VERSION 5.7 ;
BUSBITCHARS "[]" ;
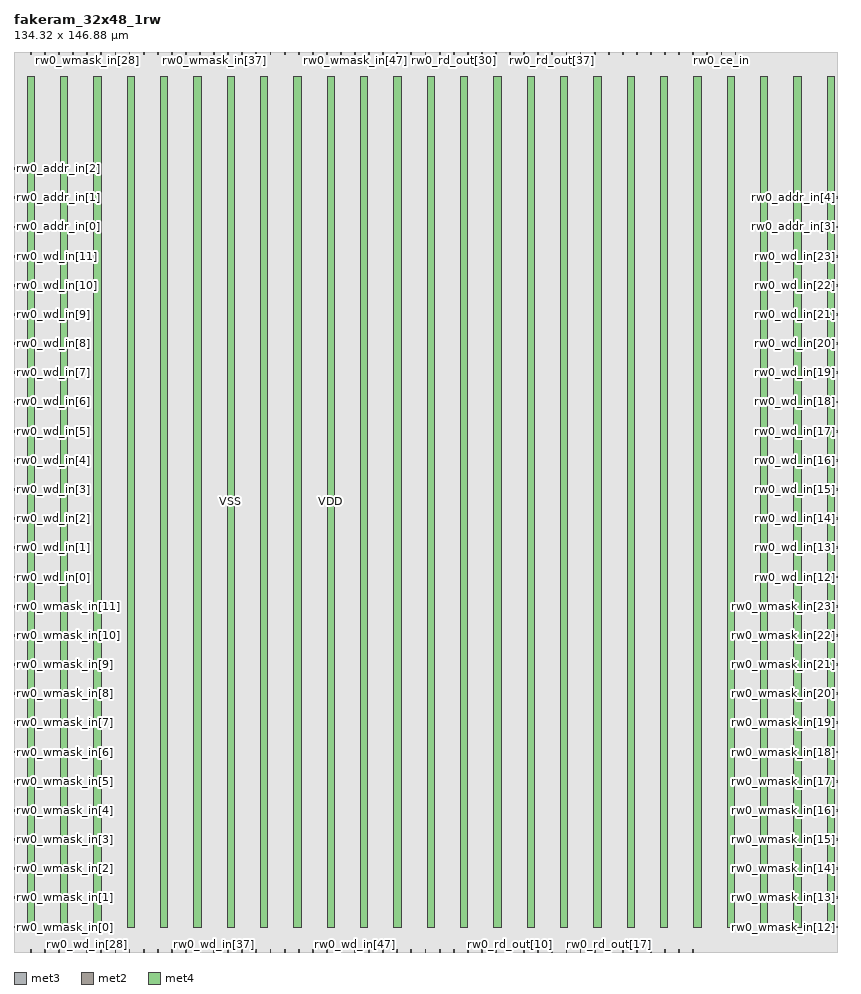
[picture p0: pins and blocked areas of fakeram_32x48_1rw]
MACRO fakeram_32x48_1rw
  FOREIGN fakeram_32x48_1rw 0 0 ;
  SYMMETRY X Y R90 ;
  SIZE 134.320 BY 146.880 ;
  CLASS BLOCK ;
  PIN rw0_wmask_in[0]
    DIRECTION INPUT ;
    USE SIGNAL ;
    SHAPE ABUTMENT ;
    PORT
      LAYER met3 ;
      RECT 0.000 3.930 0.900 4.230 ;
    END
  END rw0_wmask_in[0]
  PIN rw0_wmask_in[1]
    DIRECTION INPUT ;
    USE SIGNAL ;
    SHAPE ABUTMENT ;
    PORT
      LAYER met3 ;
      RECT 0.000 8.690 0.900 8.990 ;
    END
  END rw0_wmask_in[1]
  PIN rw0_wmask_in[2]
    DIRECTION INPUT ;
    USE SIGNAL ;
    SHAPE ABUTMENT ;
    PORT
      LAYER met3 ;
      RECT 0.000 13.450 0.900 13.750 ;
    END
  END rw0_wmask_in[2]
  PIN rw0_wmask_in[3]
    DIRECTION INPUT ;
    USE SIGNAL ;
    SHAPE ABUTMENT ;
    PORT
      LAYER met3 ;
      RECT 0.000 18.210 0.900 18.510 ;
    END
  END rw0_wmask_in[3]
  PIN rw0_wmask_in[4]
    DIRECTION INPUT ;
    USE SIGNAL ;
    SHAPE ABUTMENT ;
    PORT
      LAYER met3 ;
      RECT 0.000 22.970 0.900 23.270 ;
    END
  END rw0_wmask_in[4]
  PIN rw0_wmask_in[5]
    DIRECTION INPUT ;
    USE SIGNAL ;
    SHAPE ABUTMENT ;
    PORT
      LAYER met3 ;
      RECT 0.000 27.730 0.900 28.030 ;
    END
  END rw0_wmask_in[5]
  PIN rw0_wmask_in[6]
    DIRECTION INPUT ;
    USE SIGNAL ;
    SHAPE ABUTMENT ;
    PORT
      LAYER met3 ;
      RECT 0.000 32.490 0.900 32.790 ;
    END
  END rw0_wmask_in[6]
  PIN rw0_wmask_in[7]
    DIRECTION INPUT ;
    USE SIGNAL ;
    SHAPE ABUTMENT ;
    PORT
      LAYER met3 ;
      RECT 0.000 37.250 0.900 37.550 ;
    END
  END rw0_wmask_in[7]
  PIN rw0_wmask_in[8]
    DIRECTION INPUT ;
    USE SIGNAL ;
    SHAPE ABUTMENT ;
    PORT
      LAYER met3 ;
      RECT 0.000 42.010 0.900 42.310 ;
    END
  END rw0_wmask_in[8]
  PIN rw0_wmask_in[9]
    DIRECTION INPUT ;
    USE SIGNAL ;
    SHAPE ABUTMENT ;
    PORT
      LAYER met3 ;
      RECT 0.000 46.770 0.900 47.070 ;
    END
  END rw0_wmask_in[9]
  PIN rw0_wmask_in[10]
    DIRECTION INPUT ;
    USE SIGNAL ;
    SHAPE ABUTMENT ;
    PORT
      LAYER met3 ;
      RECT 0.000 51.530 0.900 51.830 ;
    END
  END rw0_wmask_in[10]
  PIN rw0_wmask_in[11]
    DIRECTION INPUT ;
    USE SIGNAL ;
    SHAPE ABUTMENT ;
    PORT
      LAYER met3 ;
      RECT 0.000 56.290 0.900 56.590 ;
    END
  END rw0_wmask_in[11]
  PIN rw0_wmask_in[12]
    DIRECTION INPUT ;
    USE SIGNAL ;
    SHAPE ABUTMENT ;
    PORT
      LAYER met3 ;
      RECT 133.420 3.930 134.320 4.230 ;
    END
  END rw0_wmask_in[12]
  PIN rw0_wmask_in[13]
    DIRECTION INPUT ;
    USE SIGNAL ;
    SHAPE ABUTMENT ;
    PORT
      LAYER met3 ;
      RECT 133.420 8.690 134.320 8.990 ;
    END
  END rw0_wmask_in[13]
  PIN rw0_wmask_in[14]
    DIRECTION INPUT ;
    USE SIGNAL ;
    SHAPE ABUTMENT ;
    PORT
      LAYER met3 ;
      RECT 133.420 13.450 134.320 13.750 ;
    END
  END rw0_wmask_in[14]
  PIN rw0_wmask_in[15]
    DIRECTION INPUT ;
    USE SIGNAL ;
    SHAPE ABUTMENT ;
    PORT
      LAYER met3 ;
      RECT 133.420 18.210 134.320 18.510 ;
    END
  END rw0_wmask_in[15]
  PIN rw0_wmask_in[16]
    DIRECTION INPUT ;
    USE SIGNAL ;
    SHAPE ABUTMENT ;
    PORT
      LAYER met3 ;
      RECT 133.420 22.970 134.320 23.270 ;
    END
  END rw0_wmask_in[16]
  PIN rw0_wmask_in[17]
    DIRECTION INPUT ;
    USE SIGNAL ;
    SHAPE ABUTMENT ;
    PORT
      LAYER met3 ;
      RECT 133.420 27.730 134.320 28.030 ;
    END
  END rw0_wmask_in[17]
  PIN rw0_wmask_in[18]
    DIRECTION INPUT ;
    USE SIGNAL ;
    SHAPE ABUTMENT ;
    PORT
      LAYER met3 ;
      RECT 133.420 32.490 134.320 32.790 ;
    END
  END rw0_wmask_in[18]
  PIN rw0_wmask_in[19]
    DIRECTION INPUT ;
    USE SIGNAL ;
    SHAPE ABUTMENT ;
    PORT
      LAYER met3 ;
      RECT 133.420 37.250 134.320 37.550 ;
    END
  END rw0_wmask_in[19]
  PIN rw0_wmask_in[20]
    DIRECTION INPUT ;
    USE SIGNAL ;
    SHAPE ABUTMENT ;
    PORT
      LAYER met3 ;
      RECT 133.420 42.010 134.320 42.310 ;
    END
  END rw0_wmask_in[20]
  PIN rw0_wmask_in[21]
    DIRECTION INPUT ;
    USE SIGNAL ;
    SHAPE ABUTMENT ;
    PORT
      LAYER met3 ;
      RECT 133.420 46.770 134.320 47.070 ;
    END
  END rw0_wmask_in[21]
  PIN rw0_wmask_in[22]
    DIRECTION INPUT ;
    USE SIGNAL ;
    SHAPE ABUTMENT ;
    PORT
      LAYER met3 ;
      RECT 133.420 51.530 134.320 51.830 ;
    END
  END rw0_wmask_in[22]
  PIN rw0_wmask_in[23]
    DIRECTION INPUT ;
    USE SIGNAL ;
    SHAPE ABUTMENT ;
    PORT
      LAYER met3 ;
      RECT 133.420 56.290 134.320 56.590 ;
    END
  END rw0_wmask_in[23]
  PIN rw0_wmask_in[24]
    DIRECTION INPUT ;
    USE SIGNAL ;
    SHAPE ABUTMENT ;
    PORT
      LAYER met2 ;
      RECT 2.690 146.460 2.830 146.880 ;
    END
  END rw0_wmask_in[24]
  PIN rw0_wmask_in[25]
    DIRECTION INPUT ;
    USE SIGNAL ;
    SHAPE ABUTMENT ;
    PORT
      LAYER met2 ;
      RECT 4.990 146.460 5.130 146.880 ;
    END
  END rw0_wmask_in[25]
  PIN rw0_wmask_in[26]
    DIRECTION INPUT ;
    USE SIGNAL ;
    SHAPE ABUTMENT ;
    PORT
      LAYER met2 ;
      RECT 7.290 146.460 7.430 146.880 ;
    END
  END rw0_wmask_in[26]
  PIN rw0_wmask_in[27]
    DIRECTION INPUT ;
    USE SIGNAL ;
    SHAPE ABUTMENT ;
    PORT
      LAYER met2 ;
      RECT 9.590 146.460 9.730 146.880 ;
    END
  END rw0_wmask_in[27]
  PIN rw0_wmask_in[28]
    DIRECTION INPUT ;
    USE SIGNAL ;
    SHAPE ABUTMENT ;
    PORT
      LAYER met2 ;
      RECT 11.890 146.460 12.030 146.880 ;
    END
  END rw0_wmask_in[28]
  PIN rw0_wmask_in[29]
    DIRECTION INPUT ;
    USE SIGNAL ;
    SHAPE ABUTMENT ;
    PORT
      LAYER met2 ;
      RECT 14.190 146.460 14.330 146.880 ;
    END
  END rw0_wmask_in[29]
  PIN rw0_wmask_in[30]
    DIRECTION INPUT ;
    USE SIGNAL ;
    SHAPE ABUTMENT ;
    PORT
      LAYER met2 ;
      RECT 16.490 146.460 16.630 146.880 ;
    END
  END rw0_wmask_in[30]
  PIN rw0_wmask_in[31]
    DIRECTION INPUT ;
    USE SIGNAL ;
    SHAPE ABUTMENT ;
    PORT
      LAYER met2 ;
      RECT 18.790 146.460 18.930 146.880 ;
    END
  END rw0_wmask_in[31]
  PIN rw0_wmask_in[32]
    DIRECTION INPUT ;
    USE SIGNAL ;
    SHAPE ABUTMENT ;
    PORT
      LAYER met2 ;
      RECT 21.090 146.460 21.230 146.880 ;
    END
  END rw0_wmask_in[32]
  PIN rw0_wmask_in[33]
    DIRECTION INPUT ;
    USE SIGNAL ;
    SHAPE ABUTMENT ;
    PORT
      LAYER met2 ;
      RECT 23.390 146.460 23.530 146.880 ;
    END
  END rw0_wmask_in[33]
  PIN rw0_wmask_in[34]
    DIRECTION INPUT ;
    USE SIGNAL ;
    SHAPE ABUTMENT ;
    PORT
      LAYER met2 ;
      RECT 25.690 146.460 25.830 146.880 ;
    END
  END rw0_wmask_in[34]
  PIN rw0_wmask_in[35]
    DIRECTION INPUT ;
    USE SIGNAL ;
    SHAPE ABUTMENT ;
    PORT
      LAYER met2 ;
      RECT 27.990 146.460 28.130 146.880 ;
    END
  END rw0_wmask_in[35]
  PIN rw0_wmask_in[36]
    DIRECTION INPUT ;
    USE SIGNAL ;
    SHAPE ABUTMENT ;
    PORT
      LAYER met2 ;
      RECT 30.290 146.460 30.430 146.880 ;
    END
  END rw0_wmask_in[36]
  PIN rw0_wmask_in[37]
    DIRECTION INPUT ;
    USE SIGNAL ;
    SHAPE ABUTMENT ;
    PORT
      LAYER met2 ;
      RECT 32.590 146.460 32.730 146.880 ;
    END
  END rw0_wmask_in[37]
  PIN rw0_wmask_in[38]
    DIRECTION INPUT ;
    USE SIGNAL ;
    SHAPE ABUTMENT ;
    PORT
      LAYER met2 ;
      RECT 34.890 146.460 35.030 146.880 ;
    END
  END rw0_wmask_in[38]
  PIN rw0_wmask_in[39]
    DIRECTION INPUT ;
    USE SIGNAL ;
    SHAPE ABUTMENT ;
    PORT
      LAYER met2 ;
      RECT 37.190 146.460 37.330 146.880 ;
    END
  END rw0_wmask_in[39]
  PIN rw0_wmask_in[40]
    DIRECTION INPUT ;
    USE SIGNAL ;
    SHAPE ABUTMENT ;
    PORT
      LAYER met2 ;
      RECT 39.490 146.460 39.630 146.880 ;
    END
  END rw0_wmask_in[40]
  PIN rw0_wmask_in[41]
    DIRECTION INPUT ;
    USE SIGNAL ;
    SHAPE ABUTMENT ;
    PORT
      LAYER met2 ;
      RECT 41.790 146.460 41.930 146.880 ;
    END
  END rw0_wmask_in[41]
  PIN rw0_wmask_in[42]
    DIRECTION INPUT ;
    USE SIGNAL ;
    SHAPE ABUTMENT ;
    PORT
      LAYER met2 ;
      RECT 44.090 146.460 44.230 146.880 ;
    END
  END rw0_wmask_in[42]
  PIN rw0_wmask_in[43]
    DIRECTION INPUT ;
    USE SIGNAL ;
    SHAPE ABUTMENT ;
    PORT
      LAYER met2 ;
      RECT 46.390 146.460 46.530 146.880 ;
    END
  END rw0_wmask_in[43]
  PIN rw0_wmask_in[44]
    DIRECTION INPUT ;
    USE SIGNAL ;
    SHAPE ABUTMENT ;
    PORT
      LAYER met2 ;
      RECT 48.690 146.460 48.830 146.880 ;
    END
  END rw0_wmask_in[44]
  PIN rw0_wmask_in[45]
    DIRECTION INPUT ;
    USE SIGNAL ;
    SHAPE ABUTMENT ;
    PORT
      LAYER met2 ;
      RECT 50.990 146.460 51.130 146.880 ;
    END
  END rw0_wmask_in[45]
  PIN rw0_wmask_in[46]
    DIRECTION INPUT ;
    USE SIGNAL ;
    SHAPE ABUTMENT ;
    PORT
      LAYER met2 ;
      RECT 53.290 146.460 53.430 146.880 ;
    END
  END rw0_wmask_in[46]
  PIN rw0_wmask_in[47]
    DIRECTION INPUT ;
    USE SIGNAL ;
    SHAPE ABUTMENT ;
    PORT
      LAYER met2 ;
      RECT 55.590 146.460 55.730 146.880 ;
    END
  END rw0_wmask_in[47]
  PIN rw0_wd_in[0]
    DIRECTION INPUT ;
    USE SIGNAL ;
    SHAPE ABUTMENT ;
    PORT
      LAYER met3 ;
      RECT 0.000 61.050 0.900 61.350 ;
    END
  END rw0_wd_in[0]
  PIN rw0_wd_in[1]
    DIRECTION INPUT ;
    USE SIGNAL ;
    SHAPE ABUTMENT ;
    PORT
      LAYER met3 ;
      RECT 0.000 65.810 0.900 66.110 ;
    END
  END rw0_wd_in[1]
  PIN rw0_wd_in[2]
    DIRECTION INPUT ;
    USE SIGNAL ;
    SHAPE ABUTMENT ;
    PORT
      LAYER met3 ;
      RECT 0.000 70.570 0.900 70.870 ;
    END
  END rw0_wd_in[2]
  PIN rw0_wd_in[3]
    DIRECTION INPUT ;
    USE SIGNAL ;
    SHAPE ABUTMENT ;
    PORT
      LAYER met3 ;
      RECT 0.000 75.330 0.900 75.630 ;
    END
  END rw0_wd_in[3]
  PIN rw0_wd_in[4]
    DIRECTION INPUT ;
    USE SIGNAL ;
    SHAPE ABUTMENT ;
    PORT
      LAYER met3 ;
      RECT 0.000 80.090 0.900 80.390 ;
    END
  END rw0_wd_in[4]
  PIN rw0_wd_in[5]
    DIRECTION INPUT ;
    USE SIGNAL ;
    SHAPE ABUTMENT ;
    PORT
      LAYER met3 ;
      RECT 0.000 84.850 0.900 85.150 ;
    END
  END rw0_wd_in[5]
  PIN rw0_wd_in[6]
    DIRECTION INPUT ;
    USE SIGNAL ;
    SHAPE ABUTMENT ;
    PORT
      LAYER met3 ;
      RECT 0.000 89.610 0.900 89.910 ;
    END
  END rw0_wd_in[6]
  PIN rw0_wd_in[7]
    DIRECTION INPUT ;
    USE SIGNAL ;
    SHAPE ABUTMENT ;
    PORT
      LAYER met3 ;
      RECT 0.000 94.370 0.900 94.670 ;
    END
  END rw0_wd_in[7]
  PIN rw0_wd_in[8]
    DIRECTION INPUT ;
    USE SIGNAL ;
    SHAPE ABUTMENT ;
    PORT
      LAYER met3 ;
      RECT 0.000 99.130 0.900 99.430 ;
    END
  END rw0_wd_in[8]
  PIN rw0_wd_in[9]
    DIRECTION INPUT ;
    USE SIGNAL ;
    SHAPE ABUTMENT ;
    PORT
      LAYER met3 ;
      RECT 0.000 103.890 0.900 104.190 ;
    END
  END rw0_wd_in[9]
  PIN rw0_wd_in[10]
    DIRECTION INPUT ;
    USE SIGNAL ;
    SHAPE ABUTMENT ;
    PORT
      LAYER met3 ;
      RECT 0.000 108.650 0.900 108.950 ;
    END
  END rw0_wd_in[10]
  PIN rw0_wd_in[11]
    DIRECTION INPUT ;
    USE SIGNAL ;
    SHAPE ABUTMENT ;
    PORT
      LAYER met3 ;
      RECT 0.000 113.410 0.900 113.710 ;
    END
  END rw0_wd_in[11]
  PIN rw0_wd_in[12]
    DIRECTION INPUT ;
    USE SIGNAL ;
    SHAPE ABUTMENT ;
    PORT
      LAYER met3 ;
      RECT 133.420 61.050 134.320 61.350 ;
    END
  END rw0_wd_in[12]
  PIN rw0_wd_in[13]
    DIRECTION INPUT ;
    USE SIGNAL ;
    SHAPE ABUTMENT ;
    PORT
      LAYER met3 ;
      RECT 133.420 65.810 134.320 66.110 ;
    END
  END rw0_wd_in[13]
  PIN rw0_wd_in[14]
    DIRECTION INPUT ;
    USE SIGNAL ;
    SHAPE ABUTMENT ;
    PORT
      LAYER met3 ;
      RECT 133.420 70.570 134.320 70.870 ;
    END
  END rw0_wd_in[14]
  PIN rw0_wd_in[15]
    DIRECTION INPUT ;
    USE SIGNAL ;
    SHAPE ABUTMENT ;
    PORT
      LAYER met3 ;
      RECT 133.420 75.330 134.320 75.630 ;
    END
  END rw0_wd_in[15]
  PIN rw0_wd_in[16]
    DIRECTION INPUT ;
    USE SIGNAL ;
    SHAPE ABUTMENT ;
    PORT
      LAYER met3 ;
      RECT 133.420 80.090 134.320 80.390 ;
    END
  END rw0_wd_in[16]
  PIN rw0_wd_in[17]
    DIRECTION INPUT ;
    USE SIGNAL ;
    SHAPE ABUTMENT ;
    PORT
      LAYER met3 ;
      RECT 133.420 84.850 134.320 85.150 ;
    END
  END rw0_wd_in[17]
  PIN rw0_wd_in[18]
    DIRECTION INPUT ;
    USE SIGNAL ;
    SHAPE ABUTMENT ;
    PORT
      LAYER met3 ;
      RECT 133.420 89.610 134.320 89.910 ;
    END
  END rw0_wd_in[18]
  PIN rw0_wd_in[19]
    DIRECTION INPUT ;
    USE SIGNAL ;
    SHAPE ABUTMENT ;
    PORT
      LAYER met3 ;
      RECT 133.420 94.370 134.320 94.670 ;
    END
  END rw0_wd_in[19]
  PIN rw0_wd_in[20]
    DIRECTION INPUT ;
    USE SIGNAL ;
    SHAPE ABUTMENT ;
    PORT
      LAYER met3 ;
      RECT 133.420 99.130 134.320 99.430 ;
    END
  END rw0_wd_in[20]
  PIN rw0_wd_in[21]
    DIRECTION INPUT ;
    USE SIGNAL ;
    SHAPE ABUTMENT ;
    PORT
      LAYER met3 ;
      RECT 133.420 103.890 134.320 104.190 ;
    END
  END rw0_wd_in[21]
  PIN rw0_wd_in[22]
    DIRECTION INPUT ;
    USE SIGNAL ;
    SHAPE ABUTMENT ;
    PORT
      LAYER met3 ;
      RECT 133.420 108.650 134.320 108.950 ;
    END
  END rw0_wd_in[22]
  PIN rw0_wd_in[23]
    DIRECTION INPUT ;
    USE SIGNAL ;
    SHAPE ABUTMENT ;
    PORT
      LAYER met3 ;
      RECT 133.420 113.410 134.320 113.710 ;
    END
  END rw0_wd_in[23]
  PIN rw0_wd_in[24]
    DIRECTION INPUT ;
    USE SIGNAL ;
    SHAPE ABUTMENT ;
    PORT
      LAYER met2 ;
      RECT 2.690 0.000 2.830 0.420 ;
    END
  END rw0_wd_in[24]
  PIN rw0_wd_in[25]
    DIRECTION INPUT ;
    USE SIGNAL ;
    SHAPE ABUTMENT ;
    PORT
      LAYER met2 ;
      RECT 4.990 0.000 5.130 0.420 ;
    END
  END rw0_wd_in[25]
  PIN rw0_wd_in[26]
    DIRECTION INPUT ;
    USE SIGNAL ;
    SHAPE ABUTMENT ;
    PORT
      LAYER met2 ;
      RECT 7.290 0.000 7.430 0.420 ;
    END
  END rw0_wd_in[26]
  PIN rw0_wd_in[27]
    DIRECTION INPUT ;
    USE SIGNAL ;
    SHAPE ABUTMENT ;
    PORT
      LAYER met2 ;
      RECT 9.590 0.000 9.730 0.420 ;
    END
  END rw0_wd_in[27]
  PIN rw0_wd_in[28]
    DIRECTION INPUT ;
    USE SIGNAL ;
    SHAPE ABUTMENT ;
    PORT
      LAYER met2 ;
      RECT 11.890 0.000 12.030 0.420 ;
    END
  END rw0_wd_in[28]
  PIN rw0_wd_in[29]
    DIRECTION INPUT ;
    USE SIGNAL ;
    SHAPE ABUTMENT ;
    PORT
      LAYER met2 ;
      RECT 14.190 0.000 14.330 0.420 ;
    END
  END rw0_wd_in[29]
  PIN rw0_wd_in[30]
    DIRECTION INPUT ;
    USE SIGNAL ;
    SHAPE ABUTMENT ;
    PORT
      LAYER met2 ;
      RECT 16.490 0.000 16.630 0.420 ;
    END
  END rw0_wd_in[30]
  PIN rw0_wd_in[31]
    DIRECTION INPUT ;
    USE SIGNAL ;
    SHAPE ABUTMENT ;
    PORT
      LAYER met2 ;
      RECT 18.790 0.000 18.930 0.420 ;
    END
  END rw0_wd_in[31]
  PIN rw0_wd_in[32]
    DIRECTION INPUT ;
    USE SIGNAL ;
    SHAPE ABUTMENT ;
    PORT
      LAYER met2 ;
      RECT 21.090 0.000 21.230 0.420 ;
    END
  END rw0_wd_in[32]
  PIN rw0_wd_in[33]
    DIRECTION INPUT ;
    USE SIGNAL ;
    SHAPE ABUTMENT ;
    PORT
      LAYER met2 ;
      RECT 23.390 0.000 23.530 0.420 ;
    END
  END rw0_wd_in[33]
  PIN rw0_wd_in[34]
    DIRECTION INPUT ;
    USE SIGNAL ;
    SHAPE ABUTMENT ;
    PORT
      LAYER met2 ;
      RECT 25.690 0.000 25.830 0.420 ;
    END
  END rw0_wd_in[34]
  PIN rw0_wd_in[35]
    DIRECTION INPUT ;
    USE SIGNAL ;
    SHAPE ABUTMENT ;
    PORT
      LAYER met2 ;
      RECT 27.990 0.000 28.130 0.420 ;
    END
  END rw0_wd_in[35]
  PIN rw0_wd_in[36]
    DIRECTION INPUT ;
    USE SIGNAL ;
    SHAPE ABUTMENT ;
    PORT
      LAYER met2 ;
      RECT 30.290 0.000 30.430 0.420 ;
    END
  END rw0_wd_in[36]
  PIN rw0_wd_in[37]
    DIRECTION INPUT ;
    USE SIGNAL ;
    SHAPE ABUTMENT ;
    PORT
      LAYER met2 ;
      RECT 32.590 0.000 32.730 0.420 ;
    END
  END rw0_wd_in[37]
  PIN rw0_wd_in[38]
    DIRECTION INPUT ;
    USE SIGNAL ;
    SHAPE ABUTMENT ;
    PORT
      LAYER met2 ;
      RECT 34.890 0.000 35.030 0.420 ;
    END
  END rw0_wd_in[38]
  PIN rw0_wd_in[39]
    DIRECTION INPUT ;
    USE SIGNAL ;
    SHAPE ABUTMENT ;
    PORT
      LAYER met2 ;
      RECT 37.190 0.000 37.330 0.420 ;
    END
  END rw0_wd_in[39]
  PIN rw0_wd_in[40]
    DIRECTION INPUT ;
    USE SIGNAL ;
    SHAPE ABUTMENT ;
    PORT
      LAYER met2 ;
      RECT 39.490 0.000 39.630 0.420 ;
    END
  END rw0_wd_in[40]
  PIN rw0_wd_in[41]
    DIRECTION INPUT ;
    USE SIGNAL ;
    SHAPE ABUTMENT ;
    PORT
      LAYER met2 ;
      RECT 41.790 0.000 41.930 0.420 ;
    END
  END rw0_wd_in[41]
  PIN rw0_wd_in[42]
    DIRECTION INPUT ;
    USE SIGNAL ;
    SHAPE ABUTMENT ;
    PORT
      LAYER met2 ;
      RECT 44.090 0.000 44.230 0.420 ;
    END
  END rw0_wd_in[42]
  PIN rw0_wd_in[43]
    DIRECTION INPUT ;
    USE SIGNAL ;
    SHAPE ABUTMENT ;
    PORT
      LAYER met2 ;
      RECT 46.390 0.000 46.530 0.420 ;
    END
  END rw0_wd_in[43]
  PIN rw0_wd_in[44]
    DIRECTION INPUT ;
    USE SIGNAL ;
    SHAPE ABUTMENT ;
    PORT
      LAYER met2 ;
      RECT 48.690 0.000 48.830 0.420 ;
    END
  END rw0_wd_in[44]
  PIN rw0_wd_in[45]
    DIRECTION INPUT ;
    USE SIGNAL ;
    SHAPE ABUTMENT ;
    PORT
      LAYER met2 ;
      RECT 50.990 0.000 51.130 0.420 ;
    END
  END rw0_wd_in[45]
  PIN rw0_wd_in[46]
    DIRECTION INPUT ;
    USE SIGNAL ;
    SHAPE ABUTMENT ;
    PORT
      LAYER met2 ;
      RECT 53.290 0.000 53.430 0.420 ;
    END
  END rw0_wd_in[46]
  PIN rw0_wd_in[47]
    DIRECTION INPUT ;
    USE SIGNAL ;
    SHAPE ABUTMENT ;
    PORT
      LAYER met2 ;
      RECT 55.590 0.000 55.730 0.420 ;
    END
  END rw0_wd_in[47]
  PIN rw0_rd_out[0]
    DIRECTION OUTPUT ;
    USE SIGNAL ;
    SHAPE ABUTMENT ;
    PORT
      LAYER met2 ;
      RECT 57.890 0.000 58.030 0.420 ;
    END
  END rw0_rd_out[0]
  PIN rw0_rd_out[1]
    DIRECTION OUTPUT ;
    USE SIGNAL ;
    SHAPE ABUTMENT ;
    PORT
      LAYER met2 ;
      RECT 60.190 0.000 60.330 0.420 ;
    END
  END rw0_rd_out[1]
  PIN rw0_rd_out[2]
    DIRECTION OUTPUT ;
    USE SIGNAL ;
    SHAPE ABUTMENT ;
    PORT
      LAYER met2 ;
      RECT 62.490 0.000 62.630 0.420 ;
    END
  END rw0_rd_out[2]
  PIN rw0_rd_out[3]
    DIRECTION OUTPUT ;
    USE SIGNAL ;
    SHAPE ABUTMENT ;
    PORT
      LAYER met2 ;
      RECT 64.790 0.000 64.930 0.420 ;
    END
  END rw0_rd_out[3]
  PIN rw0_rd_out[4]
    DIRECTION OUTPUT ;
    USE SIGNAL ;
    SHAPE ABUTMENT ;
    PORT
      LAYER met2 ;
      RECT 67.090 0.000 67.230 0.420 ;
    END
  END rw0_rd_out[4]
  PIN rw0_rd_out[5]
    DIRECTION OUTPUT ;
    USE SIGNAL ;
    SHAPE ABUTMENT ;
    PORT
      LAYER met2 ;
      RECT 69.390 0.000 69.530 0.420 ;
    END
  END rw0_rd_out[5]
  PIN rw0_rd_out[6]
    DIRECTION OUTPUT ;
    USE SIGNAL ;
    SHAPE ABUTMENT ;
    PORT
      LAYER met2 ;
      RECT 71.690 0.000 71.830 0.420 ;
    END
  END rw0_rd_out[6]
  PIN rw0_rd_out[7]
    DIRECTION OUTPUT ;
    USE SIGNAL ;
    SHAPE ABUTMENT ;
    PORT
      LAYER met2 ;
      RECT 73.990 0.000 74.130 0.420 ;
    END
  END rw0_rd_out[7]
  PIN rw0_rd_out[8]
    DIRECTION OUTPUT ;
    USE SIGNAL ;
    SHAPE ABUTMENT ;
    PORT
      LAYER met2 ;
      RECT 76.290 0.000 76.430 0.420 ;
    END
  END rw0_rd_out[8]
  PIN rw0_rd_out[9]
    DIRECTION OUTPUT ;
    USE SIGNAL ;
    SHAPE ABUTMENT ;
    PORT
      LAYER met2 ;
      RECT 78.590 0.000 78.730 0.420 ;
    END
  END rw0_rd_out[9]
  PIN rw0_rd_out[10]
    DIRECTION OUTPUT ;
    USE SIGNAL ;
    SHAPE ABUTMENT ;
    PORT
      LAYER met2 ;
      RECT 80.890 0.000 81.030 0.420 ;
    END
  END rw0_rd_out[10]
  PIN rw0_rd_out[11]
    DIRECTION OUTPUT ;
    USE SIGNAL ;
    SHAPE ABUTMENT ;
    PORT
      LAYER met2 ;
      RECT 83.190 0.000 83.330 0.420 ;
    END
  END rw0_rd_out[11]
  PIN rw0_rd_out[12]
    DIRECTION OUTPUT ;
    USE SIGNAL ;
    SHAPE ABUTMENT ;
    PORT
      LAYER met2 ;
      RECT 85.490 0.000 85.630 0.420 ;
    END
  END rw0_rd_out[12]
  PIN rw0_rd_out[13]
    DIRECTION OUTPUT ;
    USE SIGNAL ;
    SHAPE ABUTMENT ;
    PORT
      LAYER met2 ;
      RECT 87.790 0.000 87.930 0.420 ;
    END
  END rw0_rd_out[13]
  PIN rw0_rd_out[14]
    DIRECTION OUTPUT ;
    USE SIGNAL ;
    SHAPE ABUTMENT ;
    PORT
      LAYER met2 ;
      RECT 90.090 0.000 90.230 0.420 ;
    END
  END rw0_rd_out[14]
  PIN rw0_rd_out[15]
    DIRECTION OUTPUT ;
    USE SIGNAL ;
    SHAPE ABUTMENT ;
    PORT
      LAYER met2 ;
      RECT 92.390 0.000 92.530 0.420 ;
    END
  END rw0_rd_out[15]
  PIN rw0_rd_out[16]
    DIRECTION OUTPUT ;
    USE SIGNAL ;
    SHAPE ABUTMENT ;
    PORT
      LAYER met2 ;
      RECT 94.690 0.000 94.830 0.420 ;
    END
  END rw0_rd_out[16]
  PIN rw0_rd_out[17]
    DIRECTION OUTPUT ;
    USE SIGNAL ;
    SHAPE ABUTMENT ;
    PORT
      LAYER met2 ;
      RECT 96.990 0.000 97.130 0.420 ;
    END
  END rw0_rd_out[17]
  PIN rw0_rd_out[18]
    DIRECTION OUTPUT ;
    USE SIGNAL ;
    SHAPE ABUTMENT ;
    PORT
      LAYER met2 ;
      RECT 99.290 0.000 99.430 0.420 ;
    END
  END rw0_rd_out[18]
  PIN rw0_rd_out[19]
    DIRECTION OUTPUT ;
    USE SIGNAL ;
    SHAPE ABUTMENT ;
    PORT
      LAYER met2 ;
      RECT 101.590 0.000 101.730 0.420 ;
    END
  END rw0_rd_out[19]
  PIN rw0_rd_out[20]
    DIRECTION OUTPUT ;
    USE SIGNAL ;
    SHAPE ABUTMENT ;
    PORT
      LAYER met2 ;
      RECT 103.890 0.000 104.030 0.420 ;
    END
  END rw0_rd_out[20]
  PIN rw0_rd_out[21]
    DIRECTION OUTPUT ;
    USE SIGNAL ;
    SHAPE ABUTMENT ;
    PORT
      LAYER met2 ;
      RECT 106.190 0.000 106.330 0.420 ;
    END
  END rw0_rd_out[21]
  PIN rw0_rd_out[22]
    DIRECTION OUTPUT ;
    USE SIGNAL ;
    SHAPE ABUTMENT ;
    PORT
      LAYER met2 ;
      RECT 108.490 0.000 108.630 0.420 ;
    END
  END rw0_rd_out[22]
  PIN rw0_rd_out[23]
    DIRECTION OUTPUT ;
    USE SIGNAL ;
    SHAPE ABUTMENT ;
    PORT
      LAYER met2 ;
      RECT 110.790 0.000 110.930 0.420 ;
    END
  END rw0_rd_out[23]
  PIN rw0_rd_out[24]
    DIRECTION OUTPUT ;
    USE SIGNAL ;
    SHAPE ABUTMENT ;
    PORT
      LAYER met2 ;
      RECT 57.890 146.460 58.030 146.880 ;
    END
  END rw0_rd_out[24]
  PIN rw0_rd_out[25]
    DIRECTION OUTPUT ;
    USE SIGNAL ;
    SHAPE ABUTMENT ;
    PORT
      LAYER met2 ;
      RECT 60.190 146.460 60.330 146.880 ;
    END
  END rw0_rd_out[25]
  PIN rw0_rd_out[26]
    DIRECTION OUTPUT ;
    USE SIGNAL ;
    SHAPE ABUTMENT ;
    PORT
      LAYER met2 ;
      RECT 62.490 146.460 62.630 146.880 ;
    END
  END rw0_rd_out[26]
  PIN rw0_rd_out[27]
    DIRECTION OUTPUT ;
    USE SIGNAL ;
    SHAPE ABUTMENT ;
    PORT
      LAYER met2 ;
      RECT 64.790 146.460 64.930 146.880 ;
    END
  END rw0_rd_out[27]
  PIN rw0_rd_out[28]
    DIRECTION OUTPUT ;
    USE SIGNAL ;
    SHAPE ABUTMENT ;
    PORT
      LAYER met2 ;
      RECT 67.090 146.460 67.230 146.880 ;
    END
  END rw0_rd_out[28]
  PIN rw0_rd_out[29]
    DIRECTION OUTPUT ;
    USE SIGNAL ;
    SHAPE ABUTMENT ;
    PORT
      LAYER met2 ;
      RECT 69.390 146.460 69.530 146.880 ;
    END
  END rw0_rd_out[29]
  PIN rw0_rd_out[30]
    DIRECTION OUTPUT ;
    USE SIGNAL ;
    SHAPE ABUTMENT ;
    PORT
      LAYER met2 ;
      RECT 71.690 146.460 71.830 146.880 ;
    END
  END rw0_rd_out[30]
  PIN rw0_rd_out[31]
    DIRECTION OUTPUT ;
    USE SIGNAL ;
    SHAPE ABUTMENT ;
    PORT
      LAYER met2 ;
      RECT 73.990 146.460 74.130 146.880 ;
    END
  END rw0_rd_out[31]
  PIN rw0_rd_out[32]
    DIRECTION OUTPUT ;
    USE SIGNAL ;
    SHAPE ABUTMENT ;
    PORT
      LAYER met2 ;
      RECT 76.290 146.460 76.430 146.880 ;
    END
  END rw0_rd_out[32]
  PIN rw0_rd_out[33]
    DIRECTION OUTPUT ;
    USE SIGNAL ;
    SHAPE ABUTMENT ;
    PORT
      LAYER met2 ;
      RECT 78.590 146.460 78.730 146.880 ;
    END
  END rw0_rd_out[33]
  PIN rw0_rd_out[34]
    DIRECTION OUTPUT ;
    USE SIGNAL ;
    SHAPE ABUTMENT ;
    PORT
      LAYER met2 ;
      RECT 80.890 146.460 81.030 146.880 ;
    END
  END rw0_rd_out[34]
  PIN rw0_rd_out[35]
    DIRECTION OUTPUT ;
    USE SIGNAL ;
    SHAPE ABUTMENT ;
    PORT
      LAYER met2 ;
      RECT 83.190 146.460 83.330 146.880 ;
    END
  END rw0_rd_out[35]
  PIN rw0_rd_out[36]
    DIRECTION OUTPUT ;
    USE SIGNAL ;
    SHAPE ABUTMENT ;
    PORT
      LAYER met2 ;
      RECT 85.490 146.460 85.630 146.880 ;
    END
  END rw0_rd_out[36]
  PIN rw0_rd_out[37]
    DIRECTION OUTPUT ;
    USE SIGNAL ;
    SHAPE ABUTMENT ;
    PORT
      LAYER met2 ;
      RECT 87.790 146.460 87.930 146.880 ;
    END
  END rw0_rd_out[37]
  PIN rw0_rd_out[38]
    DIRECTION OUTPUT ;
    USE SIGNAL ;
    SHAPE ABUTMENT ;
    PORT
      LAYER met2 ;
      RECT 90.090 146.460 90.230 146.880 ;
    END
  END rw0_rd_out[38]
  PIN rw0_rd_out[39]
    DIRECTION OUTPUT ;
    USE SIGNAL ;
    SHAPE ABUTMENT ;
    PORT
      LAYER met2 ;
      RECT 92.390 146.460 92.530 146.880 ;
    END
  END rw0_rd_out[39]
  PIN rw0_rd_out[40]
    DIRECTION OUTPUT ;
    USE SIGNAL ;
    SHAPE ABUTMENT ;
    PORT
      LAYER met2 ;
      RECT 94.690 146.460 94.830 146.880 ;
    END
  END rw0_rd_out[40]
  PIN rw0_rd_out[41]
    DIRECTION OUTPUT ;
    USE SIGNAL ;
    SHAPE ABUTMENT ;
    PORT
      LAYER met2 ;
      RECT 96.990 146.460 97.130 146.880 ;
    END
  END rw0_rd_out[41]
  PIN rw0_rd_out[42]
    DIRECTION OUTPUT ;
    USE SIGNAL ;
    SHAPE ABUTMENT ;
    PORT
      LAYER met2 ;
      RECT 99.290 146.460 99.430 146.880 ;
    END
  END rw0_rd_out[42]
  PIN rw0_rd_out[43]
    DIRECTION OUTPUT ;
    USE SIGNAL ;
    SHAPE ABUTMENT ;
    PORT
      LAYER met2 ;
      RECT 101.590 146.460 101.730 146.880 ;
    END
  END rw0_rd_out[43]
  PIN rw0_rd_out[44]
    DIRECTION OUTPUT ;
    USE SIGNAL ;
    SHAPE ABUTMENT ;
    PORT
      LAYER met2 ;
      RECT 103.890 146.460 104.030 146.880 ;
    END
  END rw0_rd_out[44]
  PIN rw0_rd_out[45]
    DIRECTION OUTPUT ;
    USE SIGNAL ;
    SHAPE ABUTMENT ;
    PORT
      LAYER met2 ;
      RECT 106.190 146.460 106.330 146.880 ;
    END
  END rw0_rd_out[45]
  PIN rw0_rd_out[46]
    DIRECTION OUTPUT ;
    USE SIGNAL ;
    SHAPE ABUTMENT ;
    PORT
      LAYER met2 ;
      RECT 108.490 146.460 108.630 146.880 ;
    END
  END rw0_rd_out[46]
  PIN rw0_rd_out[47]
    DIRECTION OUTPUT ;
    USE SIGNAL ;
    SHAPE ABUTMENT ;
    PORT
      LAYER met2 ;
      RECT 110.790 146.460 110.930 146.880 ;
    END
  END rw0_rd_out[47]
  PIN rw0_addr_in[0]
    DIRECTION INPUT ;
    USE SIGNAL ;
    SHAPE ABUTMENT ;
    PORT
      LAYER met3 ;
      RECT 0.000 118.170 0.900 118.470 ;
    END
  END rw0_addr_in[0]
  PIN rw0_addr_in[1]
    DIRECTION INPUT ;
    USE SIGNAL ;
    SHAPE ABUTMENT ;
    PORT
      LAYER met3 ;
      RECT 0.000 122.930 0.900 123.230 ;
    END
  END rw0_addr_in[1]
  PIN rw0_addr_in[2]
    DIRECTION INPUT ;
    USE SIGNAL ;
    SHAPE ABUTMENT ;
    PORT
      LAYER met3 ;
      RECT 0.000 127.690 0.900 127.990 ;
    END
  END rw0_addr_in[2]
  PIN rw0_addr_in[3]
    DIRECTION INPUT ;
    USE SIGNAL ;
    SHAPE ABUTMENT ;
    PORT
      LAYER met3 ;
      RECT 133.420 118.170 134.320 118.470 ;
    END
  END rw0_addr_in[3]
  PIN rw0_addr_in[4]
    DIRECTION INPUT ;
    USE SIGNAL ;
    SHAPE ABUTMENT ;
    PORT
      LAYER met3 ;
      RECT 133.420 122.930 134.320 123.230 ;
    END
  END rw0_addr_in[4]
  PIN rw0_we_in
    DIRECTION INPUT ;
    USE SIGNAL ;
    SHAPE ABUTMENT ;
    PORT
      LAYER met2 ;
      RECT 113.090 146.460 113.230 146.880 ;
    END
  END rw0_we_in
  PIN rw0_ce_in
    DIRECTION INPUT ;
    USE SIGNAL ;
    SHAPE ABUTMENT ;
    PORT
      LAYER met2 ;
      RECT 115.390 146.460 115.530 146.880 ;
    END
  END rw0_ce_in
  PIN rw0_clk
    DIRECTION INPUT ;
    USE SIGNAL ;
    SHAPE ABUTMENT ;
    PORT
      LAYER met2 ;
      RECT 117.690 146.460 117.830 146.880 ;
    END
  END rw0_clk
  PIN VSS
    DIRECTION INOUT ;
    USE GROUND ;
    PORT
      LAYER met4 ;
      RECT 2.160 4.080 3.360 142.800 ;
      RECT 13.040 4.080 14.240 142.800 ;
      RECT 23.920 4.080 25.120 142.800 ;
      RECT 34.800 4.080 36.000 142.800 ;
      RECT 45.680 4.080 46.880 142.800 ;
      RECT 56.560 4.080 57.760 142.800 ;
      RECT 67.440 4.080 68.640 142.800 ;
      RECT 78.320 4.080 79.520 142.800 ;
      RECT 89.200 4.080 90.400 142.800 ;
      RECT 100.080 4.080 101.280 142.800 ;
      RECT 110.960 4.080 112.160 142.800 ;
      RECT 121.840 4.080 123.040 142.800 ;
      RECT 132.720 4.080 133.920 142.800 ;
    END
  END VSS
  PIN VDD
    DIRECTION INOUT ;
    USE POWER ;
    PORT
      LAYER met4 ;
      RECT 7.600 4.080 8.800 142.800 ;
      RECT 18.480 4.080 19.680 142.800 ;
      RECT 29.360 4.080 30.560 142.800 ;
      RECT 40.240 4.080 41.440 142.800 ;
      RECT 51.120 4.080 52.320 142.800 ;
      RECT 62.000 4.080 63.200 142.800 ;
      RECT 72.880 4.080 74.080 142.800 ;
      RECT 83.760 4.080 84.960 142.800 ;
      RECT 94.640 4.080 95.840 142.800 ;
      RECT 105.520 4.080 106.720 142.800 ;
      RECT 116.400 4.080 117.600 142.800 ;
      RECT 127.280 4.080 128.480 142.800 ;
    END
  END VDD
  OBS
    LAYER met1 ;
    RECT 0 0 134.320 146.880 ;
    LAYER met2 ;
    RECT 0 0 134.320 146.880 ;
    LAYER met3 ;
    RECT 0 0 134.320 146.880 ;
    LAYER met4 ;
    RECT 0 0 134.320 146.880 ;
  END
END fakeram_32x48_1rw

END LIBRARY
